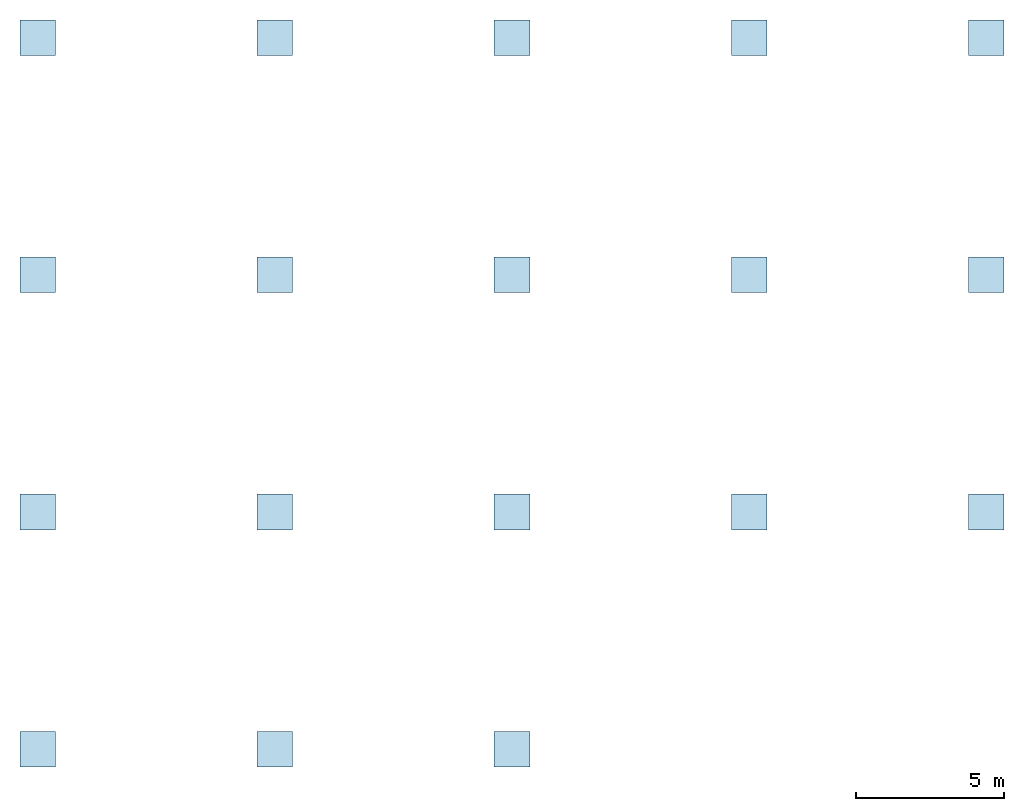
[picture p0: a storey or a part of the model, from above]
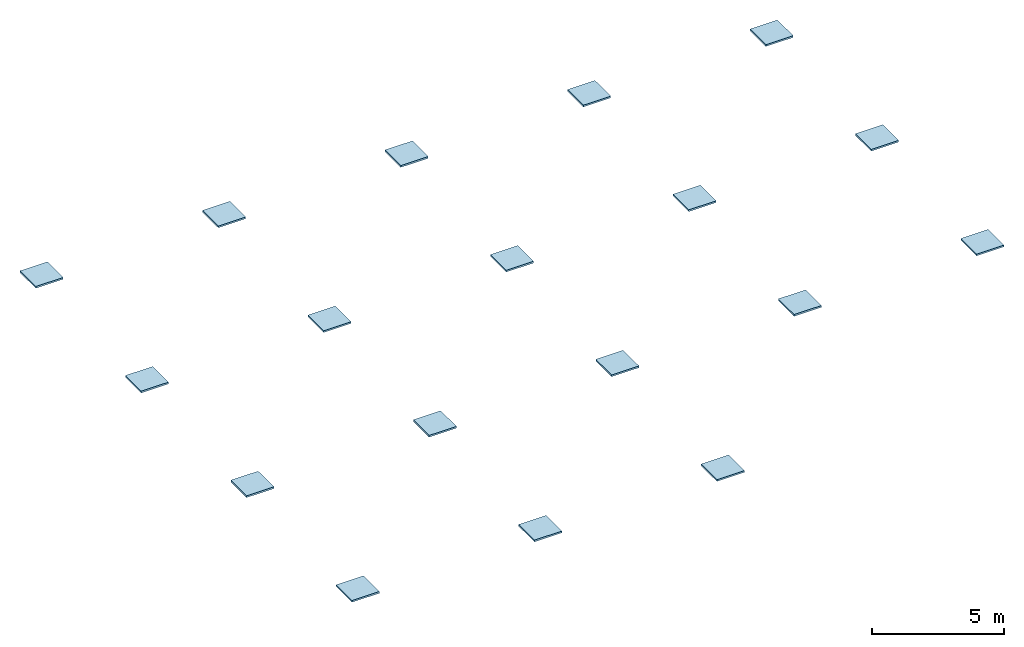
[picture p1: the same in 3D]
Properties of the parts of a building model (IFC4X3_ADD2)

# File
Description: ViewDefinition [CoordinationView], RevitIdentifiers [ContentGUID: 5ff9e910-4d03-447a-8a58-c6b140f1c449, VersionGUID: b0327820-baff-405c-b74d-c69cf85f64a2, NumberOfSaves: 25], CoordinateReference [CoordinateBase: Shared Coordinates, ProjectSite: Internal]
File name: Concrete_structure.ifc
Time: 2026-05-31T22:06:42+01:00
Written by: ODA SDAI 24.12
Made in: Autodesk Revit 25.4.0.32 (ENU) - IFC 25.4.0.27

# IfcProject, Project Number
LongName: Project Name; Phase: Project Status

# IfcSite, Default
RefLatitude: 42, 21, 31, 401672; RefLongitude: -71, -3, -24, -345703; RefElevation: 0 mm
Pset_SiteCommon - Reference: Project Information
Pset_SpaceCommon - Reference: Project Information; IsExternal: no
Other - Category: Project Information; Client Name: Client Name; Project Address: Enter address here Address Line 2; Project Issue Date: Issue Date; Project Name: Project Name; Project Number: Project Number; Project Status: Project Status
Identity Data - Building Name: Building Name; Organization Description: Organization Description; Organization Name: Organization Name

# IfcBuilding, Building Name
LongName: Building Name
Pset_BuildingCommon - Reference: Project Information; NumberOfStoreys: 7
Pset_BuildingElementProxyCommon - Reference: Project Information; IsExternal: no; sets with these values: 2
Pset_BuildingStoreyCommon - Reference: Project Information; sets with these values: 2
Other - Category: Project Information; Client Name: Client Name; Project Address: Enter address here Address Line 2; Project Issue Date: Issue Date; Project Name: Project Name; Project Number: Project Number; Project Status: Project Status
Identity Data - Building Name: Building Name; Organization Description: Organization Description; Organization Name: Organization Name

# IfcBuildingStorey: Level:8mm Head (7)
In: Building Name
Pset_BuildingStoreyCommon - Reference: 8mm Head
Pset_SpaceCommon - IsExternal: no; Reference: 8mm Head
Level Schedule - Elevation Base: Project Base Point; Structural: no
Other - Category: Levels; Family: Level; Family and Type: Level: 8mm Head; Type: 8mm Head; Type Id: 1439238
Dimensions - Computation Height: 0 mm
Identity Data - Structural: no; Building Story: yes
Other(Type) - Category: Levels; Family Name: Level
Constraints(Type) - Elevation Base: Project Base Point
Graphics(Type) - Color: 0; Line Pattern: Centre; Line Weight: 1; Symbol: M_Level Head - Circle; Symbol at End 1 Default: no; Symbol at End 2 Default: yes
Identity Data(Type) - Type Name: 8mm Head
Name | LongName = Level Schedule, Name = Identity Data, Name | Elevation (mm) = Level Schedule, Elevation (mm) = Constraints, Elevation (mm)
L-02 | L-02 | -1850
L-01 | L-01 | -800
L1 | L1 | 0 | Extents - Scope Box: Grids and Levels
L2 | L2 | 4000 | Extents - Scope Box: Grids and Levels
L3 | L3 | 8000
L4 | L4 | 12000
L5 | L5 | 16000

# IfcBeam: Concrete - Rectangular Beam:400 x 450mm (83)
Type - PredefinedType: BEAM; Material: Concrete - Cast-in-Place Concrete
Type - Other - Category: Structural Framing; Family Name: Concrete - Rectangular Beam
Type - Dimensions - b: 400 mm; h: 450 mm
Type - Identity Data - Keynote: E; Type Name: 400 x 450mm
Type - Structural - Section Shape: 0
Type - Pset_BeamCommon - LoadBearing: yes
Pset_BeamCommon - IsExternal: no; Slope: 0 deg; Roll: 0 deg; Reference: 400 x 450mm
Pset_EnvironmentalImpactIndicators - Reference: 400 x 450mm; sets with these values: 2
Structural Framing Schedule - Structural Usage: Other; Type: 400 x 450mm
Other - Family: Concrete - Rectangular Beam; Family and Type: Concrete - Rectangular Beam: 400 x 450mm; Type: 400 x 450mm; Type Id: 1693060
Constraints - Cross-Section Rotation: 0 deg; End Level Offset: 0 mm; Orientation: Normal; Start Level Offset: 0 mm
Identity Data - Has Association: no
Materials and Finishes - Structural Material: Concrete - Cast-in-Place Concrete
Phasing - Phase Created: New Construction
Structural - Rebar Cover - Other Faces: Interior (framing, columns) <40>; Structural Usage: Other; Rebar Cover - Bottom Face: Interior (framing, columns) <40>
Geometric Position - Join Status: Both joins enabled; y Justification: Origin; y Offset Value: 0 mm; yz Justification: Uniform; z Justification: Top; z Offset Value: -200 mm
Name (Concrete - Rectangular Beam:400 x 450mm:...) | In | Span (mm) = Length (mm) | Structural Framing Schedule, Reference Level = Constraints, Reference Level | Structural Framing Schedule, Elevation at Top (mm) = Dimensions, Elevation at Top (mm) | Reference Level Elevation (mm) | Work Plane | Elevation at Bottom (mm) | Volume (m3) | End Attachment Type | Start Attachment Type | Cut Length (mm)
1678168 | L2 | 8000 | L2 | 3800 | 4000 | Level : L2 | 3350 | 1.368 | End Elevation | End Elevation | 7600
1678169 | L2 | 8000 | L2 | 3800 | 4000 | Level : L2 | 3350 | 1.368 | End Elevation | End Elevation | 7600
1678170 | L2 | 8000 | L2 | 3800 | 4000 | Level : L2 | 3350 | 1.368 | End Elevation | End Elevation | 7600
1678171 | L2 | 8000 | L2 | 3800 | 4000 | Level : L2 | 3350 | 1.368 | End Elevation | End Elevation | 7600
1678173 | L2 | 8000 | L2 | 3800 | 4000 | Level : L2 | 3350 | 1.368 | End Elevation | End Elevation | 7600
1678174 | L2 | 8000 | L2 | 3800 | 4000 | Level : L2 | 3350 | 1.368 | End Elevation | End Elevation | 7600
1678175 | L2 | 8000 | L2 | 3800 | 4000 | Level : L2 | 3350 | 1.368 | End Elevation | End Elevation | 7600
1678176 | L2 | 8000 | L2 | 3800 | 4000 | Level : L2 | 3350 | 1.368 | End Elevation | End Elevation | 7600
1678177 | L2 | 8000 | L2 | 3800 | 4000 | Level : L2 | 3350 | 1.368 | End Elevation | End Elevation | 7600
1678178 | L2 | 8000 | L2 | 3800 | 4000 | Level : L2 | 3350 | 1.368 | End Elevation | End Elevation | 7600
1678179 | L2 | 8000 | L2 | 3800 | 4000 | Level : L2 | 3350 | 1.368 | End Elevation | End Elevation | 7600
1678180 | L2 | 8000 | L2 | 3800 | 4000 | Level : L2 | 3350 | 1.368 | End Elevation | End Elevation | 7600
1678181 | L2 | 8000 | L2 | 3800 | 4000 | Level : L2 | 3350 | 1.368 | End Elevation | End Elevation | 7600
1678182 | L2 | 8000 | L2 | 3800 | 4000 | Level : L2 | 3350 | 1.368 | End Elevation | End Elevation | 7600
1678183 | L2 | 8000 | L2 | 3800 | 4000 | Level : L2 | 3350 | 1.368 | End Elevation | End Elevation | 7600
1678184 | L2 | 8000 | L2 | 3800 | 4000 | Level : L2 | 3350 | 1.368 | End Elevation | End Elevation | 7600
1678185 | L2 | 8050 | L2 | 3800 | 4000 | Level : L2 | 3350 | 1.368 | End Elevation | End Elevation | 7600
1678188 | L2 | 8000 | L2 | 3800 | 4000 | Level : L2 | 3350 | 1.368 | End Elevation | End Elevation | 7600
1678189 | L2 | 8050 | L2 | 3800 | 4000 | Level : L2 | 3350 | 1.368 | End Elevation | End Elevation | 7600
1678256 | L2 | 8050 | L2 | 3800 | 4000 | Level : L2 | 3350 | 1.386 |  |  | 7700
1695331 | L2 | 8000 | L2 | 3800 | 4000 | Level : L2 | 3350 | 1.368 | End Elevation | End Elevation | 7600
1695541 | L2 | 8050 | L2 | 3800 | 4000 | Level : L2 | 3350 | 1.064 |  | End Elevation | 7600
1696909 | L4 | 8000 | L4 | 11800 | 12000 | Level : L4 | 11350 | 1.368 | End Elevation | End Elevation | 7600
1696910 | L4 | 8000 | L4 | 11800 | 12000 | Level : L4 | 11350 | 1.368 | End Elevation | End Elevation | 7600
1696911 | L4 | 8000 | L4 | 11800 | 12000 | Level : L4 | 11350 | 1.368 | End Elevation | End Elevation | 7600
1696912 | L4 | 8000 | L4 | 11800 | 12000 | Level : L4 | 11350 | 1.368 | End Elevation | End Elevation | 7600
1696914 | L4 | 8000 | L4 | 11800 | 12000 | Level : L4 | 11350 | 1.368 | End Elevation | End Elevation | 7600
1696915 | L4 | 8000 | L4 | 11800 | 12000 | Level : L4 | 11350 | 1.368 | End Elevation | End Elevation | 7600
1696916 | L4 | 8000 | L4 | 11800 | 12000 | Level : L4 | 11350 | 1.368 | End Elevation | End Elevation | 7600
1696917 | L4 | 8000 | L4 | 11800 | 12000 | Level : L4 | 11350 | 1.368 | End Elevation | End Elevation | 7600
1696918 | L4 | 8000 | L4 | 11800 | 12000 | Level : L4 | 11350 | 1.368 | End Elevation | End Elevation | 7600
1696919 | L4 | 8000 | L4 | 11800 | 12000 | Level : L4 | 11350 | 1.368 | End Elevation | End Elevation | 7600
1696920 | L4 | 8000 | L4 | 11800 | 12000 | Level : L4 | 11350 | 1.368 | End Elevation | End Elevation | 7600
1696921 | L4 | 8000 | L4 | 11800 | 12000 | Level : L4 | 11350 | 1.368 | End Elevation | End Elevation | 7600
1696922 | L4 | 8000 | L4 | 11800 | 12000 | Level : L4 | 11350 | 1.368 | End Elevation | End Elevation | 7600
1696923 | L4 | 8000 | L4 | 11800 | 12000 | Level : L4 | 11350 | 1.368 | End Elevation | End Elevation | 7600
1696924 | L4 | 8000 | L4 | 11800 | 12000 | Level : L4 | 11350 | 1.368 | End Elevation | End Elevation | 7600
1696925 | L4 | 8000 | L4 | 11800 | 12000 | Level : L4 | 11350 | 1.368 | End Elevation | End Elevation | 7600
1696926 | L4 | 8050 | L4 | 11800 | 12000 | Level : L4 | 11350 | 1.368 | End Elevation | End Elevation | 7600
1696929 | L4 | 8000 | L4 | 11800 | 12000 | Level : L4 | 11350 | 1.368 | End Elevation | End Elevation | 7600
1696930 | L4 | 8050 | L4 | 11800 | 12000 | Level : L4 | 11350 | 1.368 | End Elevation | End Elevation | 7600
1696932 | L4 | 8050 | L4 | 11800 | 12000 | Level : L4 | 11350 | 1.386 |  |  | 7700
1696940 | L4 | 8000 | L4 | 11800 | 12000 | Level : L4 | 11350 | 1.368 | End Elevation | End Elevation | 7600
1696941 | L4 | 8050 | L4 | 11800 | 12000 | Level : L4 | 11350 | 1.064 |  | End Elevation | 7600
1696977 | L3 | 8000 | L3 | 7800 | 8000 | Level : L3 | 7350 | 1.368 | End Elevation | End Elevation | 7600
1696978 | L3 | 8000 | L3 | 7800 | 8000 | Level : L3 | 7350 | 1.368 | End Elevation | End Elevation | 7600
1696979 | L3 | 8000 | L3 | 7800 | 8000 | Level : L3 | 7350 | 1.368 | End Elevation | End Elevation | 7600
1696980 | L3 | 8000 | L3 | 7800 | 8000 | Level : L3 | 7350 | 1.368 | End Elevation | End Elevation | 7600
1696982 | L3 | 8000 | L3 | 7800 | 8000 | Level : L3 | 7350 | 1.368 | End Elevation | End Elevation | 7600
1696983 | L3 | 8000 | L3 | 7800 | 8000 | Level : L3 | 7350 | 1.368 | End Elevation | End Elevation | 7600
1696984 | L3 | 8000 | L3 | 7800 | 8000 | Level : L3 | 7350 | 1.368 | End Elevation | End Elevation | 7600
1696985 | L3 | 8000 | L3 | 7800 | 8000 | Level : L3 | 7350 | 1.368 | End Elevation | End Elevation | 7600
1696986 | L3 | 8000 | L3 | 7800 | 8000 | Level : L3 | 7350 | 1.368 | End Elevation | End Elevation | 7600
1696987 | L3 | 8000 | L3 | 7800 | 8000 | Level : L3 | 7350 | 1.368 | End Elevation | End Elevation | 7600
1696988 | L3 | 8000 | L3 | 7800 | 8000 | Level : L3 | 7350 | 1.368 | End Elevation | End Elevation | 7600
1696989 | L3 | 8000 | L3 | 7800 | 8000 | Level : L3 | 7350 | 1.368 | End Elevation | End Elevation | 7600
1696990 | L3 | 8000 | L3 | 7800 | 8000 | Level : L3 | 7350 | 1.368 | End Elevation | End Elevation | 7600
1696991 | L3 | 8000 | L3 | 7800 | 8000 | Level : L3 | 7350 | 1.368 | End Elevation | End Elevation | 7600
1696992 | L3 | 8000 | L3 | 7800 | 8000 | Level : L3 | 7350 | 1.368 | End Elevation | End Elevation | 7600
1696993 | L3 | 8000 | L3 | 7800 | 8000 | Level : L3 | 7350 | 1.368 | End Elevation | End Elevation | 7600
1696994 | L3 | 8050 | L3 | 7800 | 8000 | Level : L3 | 7350 | 1.368 | End Elevation | End Elevation | 7600
1696997 | L3 | 8000 | L3 | 7800 | 8000 | Level : L3 | 7350 | 1.368 | End Elevation | End Elevation | 7600
1696998 | L3 | 8050 | L3 | 7800 | 8000 | Level : L3 | 7350 | 1.368 | End Elevation | End Elevation | 7600
1697000 | L3 | 8050 | L3 | 7800 | 8000 | Level : L3 | 7350 | 1.386 |  |  | 7700
1697008 | L3 | 8000 | L3 | 7800 | 8000 | Level : L3 | 7350 | 1.368 | End Elevation | End Elevation | 7600
1697009 | L3 | 8050 | L3 | 7800 | 8000 | Level : L3 | 7350 | 1.064 |  | End Elevation | 7600
1697216 | L5 | 8000 | L5 | 15800 | 16000 | Level : L5 | 15350 | 1.368 | End Elevation | End Elevation | 7600
1697217 | L5 | 8000 | L5 | 15800 | 16000 | Level : L5 | 15350 | 1.368 | End Elevation | End Elevation | 7600
1697218 | L5 | 8000 | L5 | 15800 | 16000 | Level : L5 | 15350 | 1.368 | End Elevation | End Elevation | 7600
1697219 | L5 | 8000 | L5 | 15800 | 16000 | Level : L5 | 15350 | 1.368 | End Elevation | End Elevation | 7600
1697221 | L5 | 8000 | L5 | 15800 | 16000 | Level : L5 | 15350 | 1.368 | End Elevation | End Elevation | 7600
1697222 | L5 | 8000 | L5 | 15800 | 16000 | Level : L5 | 15350 | 1.368 | End Elevation | End Elevation | 7600
1697223 | L5 | 8000 | L5 | 15800 | 16000 | Level : L5 | 15350 | 1.368 | End Elevation | End Elevation | 7600
1697226 | L5 | 8000 | L5 | 15800 | 16000 | Level : L5 | 15350 | 1.368 | End Elevation | End Elevation | 7600
1697228 | L5 | 8000 | L5 | 15800 | 16000 | Level : L5 | 15350 | 1.368 | End Elevation | End Elevation | 7600
1697230 | L5 | 8000 | L5 | 15800 | 16000 | Level : L5 | 15350 | 1.368 | End Elevation | End Elevation | 7600
1697232 | L5 | 8000 | L5 | 15800 | 16000 | Level : L5 | 15350 | 1.368 | End Elevation | End Elevation | 7600
1697233 | L5 | 8050 | L5 | 15800 | 16000 | Level : L5 | 15350 | 1.368 | End Elevation | End Elevation | 7600
1697236 | L5 | 8000 | L5 | 15800 | 16000 | Level : L5 | 15350 | 1.368 | End Elevation | End Elevation | 7600
1697237 | L5 | 8050 | L5 | 15800 | 16000 | Level : L5 | 15350 | 1.368 | End Elevation | End Elevation | 7600
1697239 | L5 | 8050 | L5 | 15800 | 16000 | Level : L5 | 15350 | 1.386 |  |  | 7700
1697247 | L5 | 8000 | L5 | 15800 | 16000 | Level : L5 | 15350 | 1.368 | End Elevation | End Elevation | 7600
1697248 | L5 | 8050 | L5 | 15800 | 16000 | Level : L5 | 15350 | 1.064 |  | End Elevation | 7600

# IfcBeam: Concrete - Rectangular Beam:400 x 600mm (51)
Type - PredefinedType: BEAM; Material: Concrete - Cast-in-Place Concrete
Type - Other - Category: Structural Framing; Family Name: Concrete - Rectangular Beam
Type - Dimensions - b: 400 mm; h: 600 mm
Type - Identity Data - Keynote: E; Type Name: 400 x 600mm
Type - Structural - Section Shape: 0
Type - Pset_BeamCommon - LoadBearing: yes
Pset_BeamCommon - IsExternal: no; Slope: 0 deg; Reference: 400 x 600mm; Roll: 0 deg
Pset_EnvironmentalImpactIndicators - Reference: 400 x 600mm; sets with these values: 2
Structural Framing Schedule - Type: 400 x 600mm; Structural Usage: Other
Other - Family: Concrete - Rectangular Beam; Family and Type: Concrete - Rectangular Beam: 400 x 600mm; Type: 400 x 600mm; Type Id: 1694806
Constraints - Cross-Section Rotation: 0 deg; End Level Offset: 0 mm; Orientation: Normal; Start Level Offset: 0 mm
Identity Data - Has Association: no
Materials and Finishes - Structural Material: Concrete - Cast-in-Place Concrete
Phasing - Phase Created: New Construction
Structural - Rebar Cover - Other Faces: Interior (framing, columns) <40>; Structural Usage: Other; Rebar Cover - Bottom Face: Interior (framing, columns) <40>
Geometric Position - Join Status: Both joins enabled; y Justification: Origin; y Offset Value: 0 mm; yz Justification: Uniform; z Justification: Top; z Offset Value: -200 mm
Name (Concrete - Rectangular Beam:400 x 600mm:...) | In | Span (mm) = Length (mm) | Structural Framing Schedule, Reference Level = Constraints, Reference Level | Structural Framing Schedule, Elevation at Top (mm) = Dimensions, Elevation at Top (mm) | Reference Level Elevation (mm) | Work Plane | Elevation at Bottom (mm) | Volume (m3) | Cut Length (mm)
1677369 | L1 | 8050 | L1 | -200 | 0 | Level : L1 | -800 | 1.944 | 8100
1677455 | L1 | 8000 | L1 | -200 | 0 | Level : L1 | -800 | 1.92 | 8000
1677513 | L1 | 8000 | L1 | -200 | 0 | Level : L1 | -800 | 1.92 | 8000
1677615 | L1 | 8000 | L1 | -200 | 0 | Level : L1 | -800 | 2.016 | 8400
1677616 | L1 | 8000 | L1 | -200 | 0 | Level : L1 | -800 | 1.92 | 8000
1677771 | L1 | 8050 | L1 | -200 | 0 | Level : L1 | -800 | 1.944 | 8100
1677772 | L1 | 8000 | L1 | -200 | 0 | Level : L1 | -800 | 1.92 | 8000
1677786 | L1 | 8000 | L1 | -200 | 0 | Level : L1 | -800 | 2.016 | 8400
1677787 | L1 | 8000 | L1 | -200 | 0 | Level : L1 | -800 | 1.92 | 8000
1677799 | L1 | 8000 | L1 | -200 | 0 | Level : L1 | -800 | 2.016 | 8400
1677800 | L1 | 8000 | L1 | -200 | 0 | Level : L1 | -800 | 1.92 | 8000
1677886 | L1 | 8000 | L1 | -200 | 0 | Level : L1 | -800 | 1.824 | 7600
1677905 | L1 | 8000 | L1 | -200 | 0 | Level : L1 | -800 | 1.824 | 7600
1677968 | L1 | 8000 | L1 | -200 | 0 | Level : L1 | -800 | 1.824 | 7600
1677969 | L1 | 8000 | L1 | -200 | 0 | Level : L1 | -800 | 1.824 | 7600
1677981 | L1 | 8000 | L1 | -200 | 0 | Level : L1 | -800 | 1.824 | 7600
1677982 | L1 | 8000 | L1 | -200 | 0 | Level : L1 | -800 | 1.824 | 7600
1677997 | L1 | 8000 | L1 | -200 | 0 | Level : L1 | -800 | 1.824 | 7600
1677998 | L1 | 8050 | L1 | -200 | 0 | Level : L1 | -800 | 1.824 | 7600
1678012 | L1 | 8000 | L1 | -200 | 0 | Level : L1 | -800 | 1.824 | 7600
1678013 | L1 | 8000 | L1 | -200 | 0 | Level : L1 | -800 | 1.824 | 7600
1678028 | L1 | 8000 | L1 | -200 | 0 | Level : L1 | -800 | 1.824 | 7600
1678029 | L1 | 8050 | L1 | -200 | 0 | Level : L1 | -800 | 1.848 | 7700
1678167 | L2 | 8050 | L2 | 3800 | 4000 | Level : L2 | 3200 | 1.824 | 7600 | Structural - End Attachment Type: End Elevation; Start Attachment Type: End Elevation
1678172 | L2 | 8050 | L2 | 3800 | 4000 | Level : L2 | 3200 | 1.824 | 7600 | Structural - End Attachment Type: End Elevation; Start Attachment Type: End Elevation
1678186 | L2 | 8000 | L2 | 3800 | 4000 | Level : L2 | 3200 | 1.824 | 7600 | Structural - End Attachment Type: End Elevation; Start Attachment Type: End Elevation
1678187 | L2 | 8000 | L2 | 3800 | 4000 | Level : L2 | 3200 | 1.824 | 7600 | Structural - End Attachment Type: End Elevation; Start Attachment Type: End Elevation
1685106 | L1 | 8000 | L1 | -200 | 0 | Level : L1 | -800 | 1.968 | 8300
1685107 | L1 | 8000 | L1 | -200 | 0 | Level : L1 | -800 | 1.92 | 8100
1685168 | L1 | 8000 | L1 | -200 | 0 | Level : L1 | -800 | 1.896 | 8000
1686725 | L1 | 8000 | L1 | -200 | 0 | Level : L1 | -800 | 1.824 | 7600
1695204 | L2 | 8000 | L2 | 3800 | 4000 | Level : L2 | 3200 | 1.871 | 7900 | Structural - Start Attachment Type: End Elevation
1695205 | L2 | 8050 | L2 | 3800 | 4000 | Level : L2 | 3200 | 1.848 | 7700 | Structural - End Attachment Type: End Elevation
1696908 | L4 | 8050 | L4 | 11800 | 12000 | Level : L4 | 11200 | 1.824 | 7600 | Structural - End Attachment Type: End Elevation; Start Attachment Type: End Elevation
1696913 | L4 | 8050 | L4 | 11800 | 12000 | Level : L4 | 11200 | 1.824 | 7600 | Structural - End Attachment Type: End Elevation; Start Attachment Type: End Elevation
1696927 | L4 | 8000 | L4 | 11800 | 12000 | Level : L4 | 11200 | 1.824 | 7600 | Structural - End Attachment Type: End Elevation; Start Attachment Type: End Elevation
1696928 | L4 | 8000 | L4 | 11800 | 12000 | Level : L4 | 11200 | 1.824 | 7600 | Structural - End Attachment Type: End Elevation; Start Attachment Type: End Elevation
1696938 | L4 | 8000 | L4 | 11800 | 12000 | Level : L4 | 11200 | 1.871 | 7900 | Structural - Start Attachment Type: End Elevation
1696939 | L4 | 8050 | L4 | 11800 | 12000 | Level : L4 | 11200 | 1.848 | 7700 | Structural - End Attachment Type: End Elevation
1696976 | L3 | 8050 | L3 | 7800 | 8000 | Level : L3 | 7200 | 1.824 | 7600 | Structural - End Attachment Type: End Elevation; Start Attachment Type: End Elevation
1696981 | L3 | 8050 | L3 | 7800 | 8000 | Level : L3 | 7200 | 1.824 | 7600 | Structural - End Attachment Type: End Elevation; Start Attachment Type: End Elevation
1696995 | L3 | 8000 | L3 | 7800 | 8000 | Level : L3 | 7200 | 1.824 | 7600 | Structural - End Attachment Type: End Elevation; Start Attachment Type: End Elevation
1696996 | L3 | 8000 | L3 | 7800 | 8000 | Level : L3 | 7200 | 1.824 | 7600 | Structural - End Attachment Type: End Elevation; Start Attachment Type: End Elevation
1697006 | L3 | 8000 | L3 | 7800 | 8000 | Level : L3 | 7200 | 1.871 | 7900 | Structural - Start Attachment Type: End Elevation
1697007 | L3 | 8050 | L3 | 7800 | 8000 | Level : L3 | 7200 | 1.848 | 7700 | Structural - End Attachment Type: End Elevation
1697215 | L5 | 8050 | L5 | 15800 | 16000 | Level : L5 | 15200 | 1.824 | 7600 | Structural - End Attachment Type: End Elevation; Start Attachment Type: End Elevation
1697220 | L5 | 8050 | L5 | 15800 | 16000 | Level : L5 | 15200 | 1.824 | 7600 | Structural - End Attachment Type: End Elevation; Start Attachment Type: End Elevation
1697234 | L5 | 8000 | L5 | 15800 | 16000 | Level : L5 | 15200 | 1.824 | 7600 | Structural - End Attachment Type: End Elevation; Start Attachment Type: End Elevation
1697235 | L5 | 8000 | L5 | 15800 | 16000 | Level : L5 | 15200 | 1.824 | 7600 | Structural - End Attachment Type: End Elevation; Start Attachment Type: End Elevation
1697245 | L5 | 8000 | L5 | 15800 | 16000 | Level : L5 | 15200 | 1.871 | 7900 | Structural - Start Attachment Type: End Elevation
1697246 | L5 | 8050 | L5 | 15800 | 16000 | Level : L5 | 15200 | 1.848 | 7700 | Structural - End Attachment Type: End Elevation

# IfcColumn: Concrete Square:400 x 400mm (65)
Type - PredefinedType: COLUMN; Material: Concrete - Cast-in-Place Concrete
Type - Other - Category: Structural Columns; Family Name: Concrete Square
Type - Dimensions - b: 400 mm
Type - Identity Data - Keynote: E; Type Name: 400 x 400mm
Type - Structural - Section Shape: 0
Type - Pset_ColumnCommon - LoadBearing: yes
Pset_ColumnCommon - IsExternal: no; Reference: 400 x 400mm
Pset_EnvironmentalImpactIndicators - Reference: 400 x 400mm; sets with these values: 2
Structural Column Schedule - Type: 400 x 400mm; Base Offset: 0 mm; Top Offset: 0 mm; Length: 4000 mm
Other - Family: Concrete Square; Family and Type: Concrete Square: 400 x 400mm; Type: 400 x 400mm; Type Id: 1692590
Constraints - Base Offset: 0 mm; Top Offset: 0 mm; Column Style: Vertical; Moves With Grids: yes; Room Bounding: yes
Dimensions - Length: 4000 mm
Identity Data - Has Association: no
Materials and Finishes - Structural Material: Concrete - Cast-in-Place Concrete
Phasing - Phase Created: New Construction
Structural - Rebar Cover - Other Faces: Interior (framing, columns) <40>
Name (Concrete Square:400 x 400mm:...) | In | Structural Column Schedule, Base Level = Constraints, Base Level = Level | Structural Column Schedule, Top Level = Constraints, Top Level | Volume (m3)
1676094 | L1 | L1 | L2 | 0.608 | Pset_ColumnCommon - Slope: 0 deg
1676377 | L1 | L1 | L2 | 0.608 | Pset_ColumnCommon - Slope: 0 deg
1676599 | L1 | L1 | L2 | 0.608
1676601 | L1 | L1 | L2 | 0.608
1676602 | L1 | L1 | L2 | 0.608 | Pset_ColumnCommon - Slope: 0 deg
1676603 | L1 | L1 | L2 | 0.608 | Pset_ColumnCommon - Slope: 0 deg
1676615 | L1 | L1 | L2 | 0.608 | Pset_ColumnCommon - Slope: 0 deg
1676616 | L1 | L1 | L2 | 0.608 | Pset_ColumnCommon - Slope: 0 deg
1676618 | L1 | L1 | L2 | 0.608 | Pset_ColumnCommon - Slope: 0 deg
1676619 | L1 | L1 | L2 | 0.608 | Pset_ColumnCommon - Slope: 0 deg
1676631 | L1 | L1 | L2 | 0.608 | Pset_ColumnCommon - Slope: 0 deg
1676632 | L1 | L1 | L2 | 0.608 | Pset_ColumnCommon - Slope: 0 deg
1694497 | L1 | L1 | L2 | 0.608
1694514 | L1 | L1 | L2 | 0.608
1694528 | L1 | L1 | L2 | 0.608
1694539 | L1 | L1 | L2 | 0.608
1695732 | L1 | L1 | L2 | 0.6009 | Pset_ColumnCommon - Slope: 0 deg
1696892 | L3 | L3 | L4 | 0.608
1696893 | L3 | L3 | L4 | 0.608
1696894 | L3 | L3 | L4 | 0.608 | Pset_ColumnCommon - Slope: 0 deg
1696895 | L3 | L3 | L4 | 0.608 | Pset_ColumnCommon - Slope: 0 deg
1696896 | L3 | L3 | L4 | 0.608
1696897 | L3 | L3 | L4 | 0.608
1696898 | L3 | L3 | L4 | 0.608
1696899 | L3 | L3 | L4 | 0.608
1696900 | L3 | L3 | L4 | 0.608
1696901 | L3 | L3 | L4 | 0.608
1696902 | L3 | L3 | L4 | 0.608
1696903 | L3 | L3 | L4 | 0.608
1696934 | L3 | L3 | L4 | 0.608
1696935 | L3 | L3 | L4 | 0.608
1696936 | L3 | L3 | L4 | 0.608
1696937 | L3 | L3 | L4 | 0.608
1696942 | L3 | L3 | L4 | 0.6009
1696960 | L2 | L2 | L3 | 0.608
1696961 | L2 | L2 | L3 | 0.608
1696962 | L2 | L2 | L3 | 0.608 | Pset_ColumnCommon - Slope: 0 deg
1696963 | L2 | L2 | L3 | 0.608 | Pset_ColumnCommon - Slope: 0 deg
1696964 | L2 | L2 | L3 | 0.608
1696965 | L2 | L2 | L3 | 0.608
1696966 | L2 | L2 | L3 | 0.608
1696967 | L2 | L2 | L3 | 0.608
1696968 | L2 | L2 | L3 | 0.608
1696969 | L2 | L2 | L3 | 0.608
1696970 | L2 | L2 | L3 | 0.608
1696971 | L2 | L2 | L3 | 0.608
1697002 | L2 | L2 | L3 | 0.608
1697003 | L2 | L2 | L3 | 0.608
1697004 | L2 | L2 | L3 | 0.608
1697005 | L2 | L2 | L3 | 0.608
1697010 | L2 | L2 | L3 | 0.6009
1697199 | L4 | L4 | L5 | 0.608
1697201 | L4 | L4 | L5 | 0.608 | Pset_ColumnCommon - Slope: 0 deg
1697202 | L4 | L4 | L5 | 0.608 | Pset_ColumnCommon - Slope: 0 deg
1697203 | L4 | L4 | L5 | 0.608
1697205 | L4 | L4 | L5 | 0.608
1697206 | L4 | L4 | L5 | 0.608
1697207 | L4 | L4 | L5 | 0.608
1697209 | L4 | L4 | L5 | 0.608
1697210 | L4 | L4 | L5 | 0.608
1697241 | L4 | L4 | L5 | 0.608
1697242 | L4 | L4 | L5 | 0.608
1697243 | L4 | L4 | L5 | 0.608
1697244 | L4 | L4 | L5 | 0.608
1697249 | L4 | L4 | L5 | 0.6009

# IfcFooting: M_Footing-Rectangular:1200 x 1200 x 1050mm (18)
In: L-01
Type - Material: Concrete, Cast-in-Place gray
Type - Other - Category: Structural Foundations; Family Name: M_Footing-Rectangular
Type - Dimensions - Foundation Thickness: 1050 mm; Length: 1200 mm; Width: 1200 mm
Type - Identity Data - OmniClass Number: 23.25.05.17; OmniClass Title: Shallow Foundations; Type Name: 1200 x 1200 x 1050mm
Pset_EnvironmentalImpactIndicators - Reference: 1200 x 1200 x 1050mm; sets with these values: 4
Structural Foundation Schedule - Family and Type: M_Footing-Rectangular: 1200 x 1200 x 1050mm; Level: L-01; Width: 1200 mm; Foundation Thickness: 1050 mm
Other - Family: M_Footing-Rectangular; Family and Type: M_Footing-Rectangular: 1200 x 1200 x 1050mm; Type: 1200 x 1200 x 1050mm; Type Id: 1681900
Constraints - Moves With Grids: yes; Height Offset From Level: 0 mm; Host: Level : L-01; Level: L-01
Dimensions - Area: 1.44 m2; Elevation at Bottom: -1850 mm; Elevation at Bottom Survey: -1850 mm; Elevation at Top: -800 mm; Elevation at Top Survey: -800 mm; Volume: 1.512 m3
Identity Data - Has Association: no
Materials and Finishes - Structural Material: Concrete, Cast-in-Place gray
Phasing - Phase Created: New Construction
Structural - Rebar Cover - Other Faces: Interior (framing, columns) <40>; Rebar Cover - Bottom Face: Interior (framing, columns) <40>; Rebar Cover - Top Face: Interior (framing, columns) <40>
Name (M_Footing-Rectangular:1200 x 1200 x 1050mm:...)
1681903
1682150
1682573
1682690
1682945
1683199
1683200
1683201
1683202
1683203
1683213
1683214
1683215
1683216
1683217
1683227
1683228
1683231

# IfcOpeningElement (3)
PredefinedType: OPENING
Pset_EnvironmentalImpactIndicators - Reference: Generic 200mm; sets with these values: 2
Other - Category: Lines: <Sketch>; Concrete Cantilever: 0 mm; Steel Cantilever: 0 mm
Constraints - Defines Constant Height: no; Defines Slope: no; Offset From Base: 0 mm
Dimensions - Length: 3600 mm; Slope: 0.0833333
Name (Floor:Generic 200mm:...) | In
1659782 | L2
1659782 | L3
1659782 | L4

# IfcSlab: Floor:Blinding concrete 80mm (55)
Type - PredefinedType: FLOOR; Material: Concrete - Cast-in-Place Concrete 80 mm
Type - Other - Category: Floors; Family Name: Floor
Type - Construction - Function: Interior; Default Thickness: 80 mm
Type - Graphics - Coarse Scale Fill Color: 0
Type - Identity Data - Description: Generic Floor (Material By Category), 300mm thick; Type Name: Blinding concrete 80mm
Type - Materials and Finishes - Structural Material: Concrete - Cast-in-Place Concrete
Type - Analytical Properties - Absorptance: 0.7; Roughness: 3
Type - Pset_ReinforcementBarPitchOfSlab - Description: Generic Floor (Material By Category), 300mm thick
Pset_EnvironmentalImpactIndicators - Reference: Blinding concrete 80mm; sets with these values: 2
Pset_SlabCommon - IsExternal: no; LoadBearing: yes; PitchAngle: 0 deg; Reference: Blinding concrete 80mm
Other - Family: Floor; Family and Type: Floor: Blinding concrete 80mm; Type: Blinding concrete 80mm; Type Id: 1690434
Constraints - Room Bounding: yes; Related to Mass: no
Dimensions - Core Thickness: 80 mm; Thickness: 80 mm
Identity Data - Has Association: no
Phasing - Phase Created: New Construction
Structural - Structural: yes; Rebar Cover - Bottom Face: Interior (framing, columns) <40>
Name (Floor:Blinding concrete 80mm:...) | In | Level | Height Offset From Level (mm) | Area (m2) | Elevation at Bottom (mm) = Elevation at Bottom Core (mm) = Elevation at Bottom Survey (mm) | Elevation at Top (mm) = Elevation at Top Core (mm) = Elevation at Top Survey (mm) | Perimeter (mm) | Volume (m3) | Rebar Cover - Top Face | Rebar Cover - Other Faces
1698274 | L1 | L1 | -200 | 57.76 | -280 | -200 | 30400 | 4.6208 | Interior (framing, columns) <40>
1698448 | L1 | L1 | -200 | 57.76 | -280 | -200 | 30400 | 4.6208 | Interior (framing, columns) <40>
1698465 | L1 | L1 | -200 | 57.76 | -280 | -200 | 30400 | 4.6208 | Interior (framing, columns) <40>
1698482 | L1 | L1 | -200 | 57.76 | -280 | -200 | 30400 | 4.6208 | Interior (framing, columns) <40>
1698497 | L1 | L1 | -200 | 57.76 | -280 | -200 | 30400 | 4.6208 | Interior (framing, columns) <40>
1698514 | L1 | L1 | -200 | 57.76 | -280 | -200 | 30400 | 4.6208 | Interior (framing, columns) <40>
1698531 | L1 | L1 | -200 | 57.76 | -280 | -200 | 30400 | 4.6208 | Interior (framing, columns) <40>
1698546 | L1 | L1 | -200 | 57.76 | -280 | -200 | 30400 | 4.6208 | Interior (framing, columns) <40>
1698565 | L1 | L1 | -200 | 57.76 | -280 | -200 | 30400 | 4.6208 | Interior (framing, columns) <40>
1698580 | L1 | L1 | -200 | 57.76 | -280 | -200 | 30400 | 4.6208 | Interior (framing, columns) <40>
1699005 | L-01 | L-01 | 0 | 2.72 | -880 | -800 | 14400 | 0.2176 |  | Interior (framing, columns) <40>
1699082 | L-01 | L-01 | 0 | 2.72 | -880 | -800 | 14400 | 0.2176 |  | Interior (framing, columns) <40>
1699099 | L-01 | L-01 | 0 | 2.72 | -880 | -800 | 14400 | 0.2176 |  | Interior (framing, columns) <40>
1699118 | L-01 | L-01 | 0 | 2.72 | -880 | -800 | 14400 | 0.2176 |  | Interior (framing, columns) <40>
1699337 | L-01 | L-01 | 0 | 2.72 | -880 | -800 | 14400 | 0.2176 |  | Interior (framing, columns) <40>
1699356 | L-01 | L-01 | 0 | 2.72 | -880 | -800 | 14400 | 0.2176 |  | Interior (framing, columns) <40>
1699373 | L-01 | L-01 | 0 | 2.72 | -880 | -800 | 14400 | 0.2176 |  | Interior (framing, columns) <40>
1699392 | L-01 | L-01 | 0 | 2.72 | -880 | -800 | 14400 | 0.2176 |  | Interior (framing, columns) <40>
1699413 | L-01 | L-01 | 0 | 2.72 | -880 | -800 | 14400 | 0.2176 |  | Interior (framing, columns) <40>
1699430 | L-01 | L-01 | 0 | 2.72 | -880 | -800 | 14400 | 0.2176 |  | Interior (framing, columns) <40>
1699445 | L-01 | L-01 | 0 | 2.72 | -880 | -800 | 14400 | 0.2176 |  | Interior (framing, columns) <40>
1699477 | L-01 | L-01 | 0 | 2.72 | -880 | -800 | 14400 | 0.2176 |  | Interior (framing, columns) <40>
1699498 | L-01 | L-01 | 0 | 2.72 | -880 | -800 | 14400 | 0.2176 |  | Interior (framing, columns) <40>
1699514 | L-01 | L-01 | 0 | 2.72 | -880 | -800 | 14400 | 0.2176 |  | Interior (framing, columns) <40>
1699592 | L-01 | L-01 | 0 | 2.72 | -880 | -800 | 14400 | 0.2176 |  | Interior (framing, columns) <40>
1699607 | L-01 | L-01 | 0 | 2.72 | -880 | -800 | 14400 | 0.2176 |  | Interior (framing, columns) <40>
1699624 | L-01 | L-01 | 0 | 2.72 | -880 | -800 | 14400 | 0.2176 |  | Interior (framing, columns) <40>
1699641 | L-01 | L-01 | 0 | 2.72 | -880 | -800 | 14400 | 0.2176 |  | Interior (framing, columns) <40>
1699658 | L-01 | L-01 | 0 | 2.72 | -880 | -800 | 14400 | 0.2176 |  | Interior (framing, columns) <40>
1699677 | L-01 | L-01 | 0 | 2.72 | -880 | -800 | 14400 | 0.2176 |  | Interior (framing, columns) <40>
1699694 | L-01 | L-01 | 0 | 2.72 | -880 | -800 | 14400 | 0.2176 |  | Interior (framing, columns) <40>
1699713 | L-01 | L-01 | 0 | 2.72 | -880 | -800 | 14400 | 0.2176 |  | Interior (framing, columns) <40>
1699728 | L-01 | L-01 | 0 | 2.72 | -880 | -800 | 14400 | 0.2176 |  | Interior (framing, columns) <40>
1699762 | L-01 | L-01 | 0 | 2.72 | -880 | -800 | 14400 | 0.2176 |  | Interior (framing, columns) <40>
1699779 | L-01 | L-01 | 0 | 2.72 | -880 | -800 | 14400 | 0.2176 |  | Interior (framing, columns) <40>
1699796 | L-01 | L-01 | 0 | 2.72 | -880 | -800 | 14400 | 0.2176 |  | Interior (framing, columns) <40>
1699823 | L-01 | L-01 | 0 | 2.72 | -880 | -800 | 14400 | 0.2176 |  | Interior (framing, columns) <40>
1699975 | L-02 | L-02 | 0 | 1.44 | -1930 | -1850 | 4800 | 0.1152 | Interior (framing, columns) <40> | Interior (framing, columns) <40>
1700016 | L-02 | L-02 | 0 | 1.44 | -1930 | -1850 | 4800 | 0.1152 | Interior (framing, columns) <40> | Interior (framing, columns) <40>
1700031 | L-02 | L-02 | 0 | 1.44 | -1930 | -1850 | 4800 | 0.1152 | Interior (framing, columns) <40> | Interior (framing, columns) <40>
1700048 | L-02 | L-02 | 0 | 1.44 | -1930 | -1850 | 4800 | 0.1152 | Interior (framing, columns) <40> | Interior (framing, columns) <40>
1700065 | L-02 | L-02 | 0 | 1.44 | -1930 | -1850 | 4800 | 0.1152 | Interior (framing, columns) <40> | Interior (framing, columns) <40>
1700080 | L-02 | L-02 | 0 | 1.44 | -1930 | -1850 | 4800 | 0.1152 | Interior (framing, columns) <40> | Interior (framing, columns) <40>
1700095 | L-02 | L-02 | 0 | 1.44 | -1930 | -1850 | 4800 | 0.1152 | Interior (framing, columns) <40> | Interior (framing, columns) <40>
1700112 | L-02 | L-02 | 0 | 1.44 | -1930 | -1850 | 4800 | 0.1152 | Interior (framing, columns) <40> | Interior (framing, columns) <40>
1700127 | L-02 | L-02 | 0 | 1.44 | -1930 | -1850 | 4800 | 0.1152 | Interior (framing, columns) <40> | Interior (framing, columns) <40>
1700144 | L-02 | L-02 | 0 | 1.44 | -1930 | -1850 | 4800 | 0.1152 | Interior (framing, columns) <40> | Interior (framing, columns) <40>
1700161 | L-02 | L-02 | 0 | 1.44 | -1930 | -1850 | 4800 | 0.1152 | Interior (framing, columns) <40> | Interior (framing, columns) <40>
1700174 | L-02 | L-02 | 0 | 1.44 | -1930 | -1850 | 4800 | 0.1152 | Interior (framing, columns) <40> | Interior (framing, columns) <40>
1700187 | L-02 | L-02 | 0 | 1.44 | -1930 | -1850 | 4800 | 0.1152 | Interior (framing, columns) <40> | Interior (framing, columns) <40>
1700204 | L-02 | L-02 | 0 | 1.44 | -1930 | -1850 | 4800 | 0.1152 | Interior (framing, columns) <40> | Interior (framing, columns) <40>
1700221 | L-02 | L-02 | 0 | 1.44 | -1930 | -1850 | 4800 | 0.1152 | Interior (framing, columns) <40> | Interior (framing, columns) <40>
1700240 | L-02 | L-02 | 0 | 1.44 | -1930 | -1850 | 4800 | 0.1152 | Interior (framing, columns) <40> | Interior (framing, columns) <40>
1700257 | L-02 | L-02 | 0 | 1.44 | -1930 | -1850 | 4800 | 0.1152 | Interior (framing, columns) <40> | Interior (framing, columns) <40>
1700272 | L-02 | L-02 | 0 | 1.44 | -1930 | -1850 | 4800 | 0.1152 | Interior (framing, columns) <40> | Interior (framing, columns) <40>

# IfcSlab: Floor:Generic 200mm (5)
Type - PredefinedType: FLOOR; Material: Default Floor 200 mm
Type - Other - Category: Floors; Family Name: Floor
Type - Construction - Default Thickness: 200 mm; Function: Interior
Type - Graphics - Coarse Scale Fill Color: 0
Type - Identity Data - Description: Generic Floor (Material By Category), 300mm thick; Type Name: Generic 200mm
Type - Analytical Properties - Absorptance: 0.7; Roughness: 3
Type - Pset_ReinforcementBarPitchOfSlab - Description: Generic Floor (Material By Category), 300mm thick
Pset_EnvironmentalImpactIndicators - Reference: Generic 200mm; sets with these values: 2
Pset_SlabCommon - IsExternal: no; LoadBearing: yes; Reference: Generic 200mm; PitchAngle: 0 deg
Other - Family: Floor; Family and Type: Floor: Generic 200mm; Type: Generic 200mm; Type Id: 1659782
Constraints - Room Bounding: yes; Related to Mass: no; Height Offset From Level: 0 mm
Dimensions - Core Thickness: 200 mm; Thickness: 200 mm
Identity Data - Has Association: no
Phasing - Phase Created: New Construction
Structural - Rebar Cover - Other Faces: Interior (framing, columns) <40>; Structural: yes; Rebar Cover - Bottom Face: Interior (framing, columns) <40>; Rebar Cover - Top Face: Interior (framing, columns) <40>
Name (Floor:Generic 200mm:...) | In | Level | Area (m2) | Elevation at Bottom (mm) = Elevation at Bottom Core (mm) = Elevation at Bottom Survey (mm) | Elevation at Top (mm) = Elevation at Top Core (mm) = Elevation at Top Survey (mm) | Perimeter (mm) | Volume (m3)
1696004 | L1 | L1 | 662.56 | -200 | 0 | 113600 | 132.512
1697013 | L2 | L2 | 635.2 | 3800 | 4000 | 136000 | 127.04
1697401 | L3 | L3 | 635.2 | 7800 | 8000 | 136000 | 127.04
1697418 | L4 | L4 | 635.2 | 11800 | 12000 | 136000 | 127.04
1697434 | L5 | L5 | 531.36 | 15800 | 16000 | 97600 | 106.272

# IfcSlab: Floor:Gravel 300 mm (10)
In: L1
Type - PredefinedType: FLOOR; Material: Gravel 300 mm
Type - Other - Category: Floors; Family Name: Floor
Type - Construction - Function: Interior; Default Thickness: 300 mm
Type - Graphics - Coarse Scale Fill Color: 0
Type - Identity Data - Description: Generic Floor (Material By Category), 300mm thick; Type Name: Gravel 300 mm
Type - Materials and Finishes - Structural Material: Gravel
Type - Analytical Properties - Absorptance: 0.7; Roughness: 3; Heat Transfer Coefficient (U): 1.2 kg/K/s3; Thermal Mass: 463680 kg/K/s2; Thermal Resistance (R): 0.833333 s3*K/kg
Type - Pset_ReinforcementBarPitchOfSlab - Description: Generic Floor (Material By Category), 300mm thick
Type - Pset_SlabCommon - ThermalTransmittance: 1.2 kg/K/s3
Pset_EnvironmentalImpactIndicators - Reference: Gravel 300 mm; sets with these values: 2
Pset_SlabCommon - IsExternal: no; LoadBearing: yes; PitchAngle: 0 deg; Reference: Gravel 300 mm
Other - Family: Floor; Family and Type: Floor: Gravel 300 mm; Type: Gravel 300 mm; Type Id: 1690866
Constraints - Level: L1; Room Bounding: yes; Related to Mass: no; Height Offset From Level: -280 mm
Dimensions - Area: 57.76 m2; Core Thickness: 300 mm; Elevation at Bottom: -580 mm; Elevation at Bottom Core: -580 mm; Elevation at Bottom Survey: -580 mm; Elevation at Top: -280 mm; Elevation at Top Core: -280 mm; Elevation at Top Survey: -280 mm; Perimeter: 30400 mm; Thickness: 300 mm; Volume: 17.328 m3
Identity Data - Has Association: no
Phasing - Phase Created: New Construction
Structural - Structural: yes; Rebar Cover - Bottom Face: Interior (framing, columns) <40>; Rebar Cover - Top Face: Interior (framing, columns) <40>
Name (Floor:Gravel 300 mm:...)
1698639
1698729
1698748
1698767
1698784
1698801
1698818
1698835
1698856
1698873

# IfcWall: Basic Wall:Generic - 200mm (4)
Type - PredefinedType: STANDARD; Material: Default Wall 200 mm
Type - Other - Category: Walls; Family Name: Basic Wall
Type - Construction - Function: Exterior; Wrapping at Inserts: Do not wrap; Width: 200 mm
Type - Graphics - Coarse Scale Fill Color: 0
Type - Identity Data - Assembly Code: B2010; Assembly Description: Exterior Walls; Description: Generic Wall (Material By Category), 200mm thick; Type Mark: G06; Type Name: Generic - 200mm
Type - Analytical Properties - Absorptance: 0.7; Roughness: 3
Type - Pset_ReinforcementBarPitchOfWall - Description: Generic Wall (Material By Category), 200mm thick
Classification: B2010 Exterior Walls (Uniformat)
Pset_EnvironmentalImpactIndicators - Reference: Generic - 200mm; sets with these values: 2
Pset_WallCommon - LoadBearing: yes; IsExternal: yes; ExtendToStructure: no; Reference: Generic - 200mm
Structural Wall Schedule - Base Offset: 0 mm; Structural Usage: Bearing; Type: Generic - 200mm; Top Offset: -450 mm; Width: 200 mm
Other - Family: Basic Wall; Family and Type: Basic Wall: Generic - 200mm; Type: Generic - 200mm; Type Id: 441451
Constraints - Base Offset: 0 mm; Room Bounding: yes; Base Extension Distance: 0 mm; Base is Attached: no; Location Line: Wall Centerline; Related to Mass: no; Top Extension Distance: 0 mm; Top is Attached: no; Top Offset: -450 mm; Unconnected Height: 3550 mm
Dimensions - Area: 27.3705 m2; Length: 7860 mm; Volume: 5.4741 m3
Identity Data - Has Association: no
Phasing - Phase Created: New Construction
Structural - Rebar Cover - Other Faces: Interior (framing, columns) <40>; Structural Usage: Bearing; Rebar Cover - Exterior Face: Interior (framing, columns) <40>; Rebar Cover - Interior Face: Interior (framing, columns) <40>; Structural: yes
Cross-Section Definition - Cross-Section: Vertical
Name (Basic Wall:Generic - 200mm:...) | In | Structural Wall Schedule, Base Constraint = Constraints, Base Constraint | Structural Wall Schedule, Top Constraint = Constraints, Top Constraint
1677219 | L1 | L1 | Up to level: L2
1696905 | L3 | L3 | Up to level: L4
1696973 | L2 | L2 | Up to level: L3
1697212 | L4 | L4 | Up to level: L5

# IfcWall: Basic Wall:Generic - 300mm (8)
Type - PredefinedType: STANDARD; Material: Default Wall 300 mm
Type - Other - Category: Walls; Family Name: Basic Wall
Type - Construction - Function: Exterior; Width: 300 mm; Wrapping at Inserts: Do not wrap
Type - Graphics - Coarse Scale Fill Color: 0
Type - Identity Data - Assembly Code: B2010; Assembly Description: Exterior Walls; Description: Generic Wall (Material By Category), 300mm thick; Type Mark: G09; Type Name: Generic - 300mm
Type - Analytical Properties - Absorptance: 0.7; Roughness: 3
Type - Pset_ReinforcementBarPitchOfWall - Description: Generic Wall (Material By Category), 300mm thick
Classification: B2010 Exterior Walls (Uniformat)
Pset_EnvironmentalImpactIndicators - Reference: Generic - 300mm; sets with these values: 2
Pset_WallCommon - LoadBearing: yes; Reference: Generic - 300mm; IsExternal: yes; ExtendToStructure: no
Structural Wall Schedule - Base Offset: 0 mm; Type: Generic - 300mm; Width: 300 mm; Structural Usage: Bearing
Other - Family: Basic Wall; Family and Type: Basic Wall: Generic - 300mm; Type: Generic - 300mm; Type Id: 441453
Constraints - Base Offset: 0 mm; Room Bounding: yes; Base Extension Distance: 0 mm; Base is Attached: no; Location Line: Wall Centerline; Related to Mass: no; Top Extension Distance: 0 mm; Top is Attached: no
Identity Data - Has Association: no
Phasing - Phase Created: New Construction
Structural - Rebar Cover - Other Faces: Interior (framing, columns) <40>; Structural Usage: Bearing; Rebar Cover - Exterior Face: Interior (framing, columns) <40>; Rebar Cover - Interior Face: Interior (framing, columns) <40>; Structural: yes
Cross-Section Definition - Cross-Section: Vertical
Name (Basic Wall:Generic - 300mm:...) | In | Structural Wall Schedule, Base Constraint = Constraints, Base Constraint | Structural Wall Schedule, Top Constraint = Constraints, Top Constraint | Structural Wall Schedule, Top Offset (mm) = Constraints, Top Offset (mm) | Unconnected Height (mm) | Area (m2) | Length (mm) | Volume (m3)
1676973 | L1 | L1 | Up to level: L2 | -650 | 3350 | 25.46 | 7600 | 7.638
1688745 | L1 | L1 | Up to level: L2 | -800 | 3200 | 49.92 | 15600 | 14.976
1696904 | L3 | L3 | Up to level: L4 | -650 | 3350 | 25.46 | 7600 | 7.638
1696933 | L3 | L3 | Up to level: L4 | -800 | 3200 | 49.92 | 15600 | 14.976
1696972 | L2 | L2 | Up to level: L3 | -650 | 3350 | 25.46 | 7600 | 7.638
1697001 | L2 | L2 | Up to level: L3 | -800 | 3200 | 49.92 | 15600 | 14.976
1697211 | L4 | L4 | Up to level: L5 | -650 | 3350 | 25.46 | 7600 | 7.638
1697240 | L4 | L4 | Up to level: L5 | -800 | 3200 | 49.92 | 15600 | 14.976

# Material: Concrete - Cast-in-Place Concrete
Identity - Category: Concrete; Class: Concrete
Structural - Name: Normal Weight Concrete - 35 MPa; Type: Concrete; Behavior: Isotropic; TensileStrength: 448.159 Pa; ConcreteCompression: 35000000 Pa; ShearStrengthModification: 1; ThermallyTreated: no
Pset_MaterialCommon - MassDensity: 2406.53 kg/m3
Pset_MaterialMechanical - YoungModulus: 29910000000 kg/s2/m; ShearModulus: 12463000000 kg/s2/m; PoissonRatio: 0.2; ThermalExpansionCoefficient: 0.0000099 1/K
Pset_MaterialSteel - YieldStress: 344.738 Pa
Other - Category: Materials
Materials and Finishes - Color: 12632256; Glow: no; Material Type: Concrete; Name: Concrete - Cast-in-Place Concrete; Shininess: 128; Smoothness: 50; Transparency: 0

# Material: Default Wall
Identity - Category: Miscellaneous; Class: Miscellaneous
Other - Category: Materials
Identity Data - Cost: 0
Materials and Finishes - Glow: no; Transparency: 0; Color: 12632256; Name: Default Wall; Shininess: 10; Smoothness: 50

# Material: Concrete, Cast-in-Place gray
Identity - Category: Concrete; Class: Concrete
Structural - ShearStrengthModification: 1; Name: Concrete(1); Description: Default Concrete f'c=24.0 Mpa; Keywords: :structural:concrete; Type: Concrete; SubClass: Standard; Source: Autodesk; Behavior: Isotropic; TensileStrength: 2413294 Pa; ConcreteCompression: 24132938 Pa; ThermallyTreated: no
Thermal - Name: Concrete; Description: Concrete, stone aggregate; Keywords: thermal:solid; Type: Solid; SubClass: Concrete; Source: Autodesk; Density: 2300 kg/m3; Emissivity: 0.95; Behavior: Isotropic; TransmitsLight: no; Permeability: 0 s/m; Reflectivity: 0; ElectricalResistivity: 2000000 kg*m3/s3/A2
Pset_MaterialCommon - Porosity: 0.001; MassDensity: 2407.31 kg/m3
Pset_MaterialMechanical - YoungModulus: 23250000000 kg/s2/m; ShearModulus: 9964000000 kg/s2/m; PoissonRatio: 0.167; ThermalExpansionCoefficient: 0.00001 1/K
Pset_MaterialSteel - YieldStress: 2413294 Pa
Pset_MaterialThermal - SpecificHeatCapacity: 657 m2/K/s2; ThermalConductivity: 1.046
Other - Category: Materials
Identity Data - Cost: 0; Description: Cast-in-place concrete
Materials and Finishes - Glow: no; Material Type: Concrete; Transparency: 0; Color: 12632256; Name: Concrete, Cast-in-Place gray; Shininess: 64; Smoothness: 50

# Material: Default Floor
Identity - Category: Miscellaneous; Class: Miscellaneous
Other - Category: Materials
Identity Data - Cost: 0
Materials and Finishes - Glow: no; Transparency: 0; Shininess: 10; Color: 8421504; Name: Default Floor; Smoothness: 50

# Material: Gravel
Identity - Category: Misc; Class: Generic
Structural - Name: Gravel; Description: Basic structural asset.; Keywords: stone:ballast:structural:basic; Type: Basic; Behavior: Isotropic
Thermal - Permeability: 0 s/m; Reflectivity: 0; Name: Gravel; Description: Gravel; Keywords: Crushed Stone:ballast:aggregate:thermal:solid; Type: Solid; SubClass: Earth; Source: Autodesk; Density: 1840 kg/m3; Emissivity: 0.9; Behavior: Isotropic; TransmitsLight: no; ElectricalResistivity: 15000 kg*m3/s3/A2
Pset_MaterialCommon - Porosity: 0.001; MassDensity: 1840 kg/m3
Pset_MaterialThermal - SpecificHeatCapacity: 840 m2/K/s2; ThermalConductivity: 0.36
Other - Category: Materials
Identity Data - Cost: 0; Description: Crushed stone or gravel
Materials and Finishes - Glow: no; Transparency: 0; Color: 7895160; Material Type: Other; Name: Gravel; Shininess: 64; Smoothness: 50
